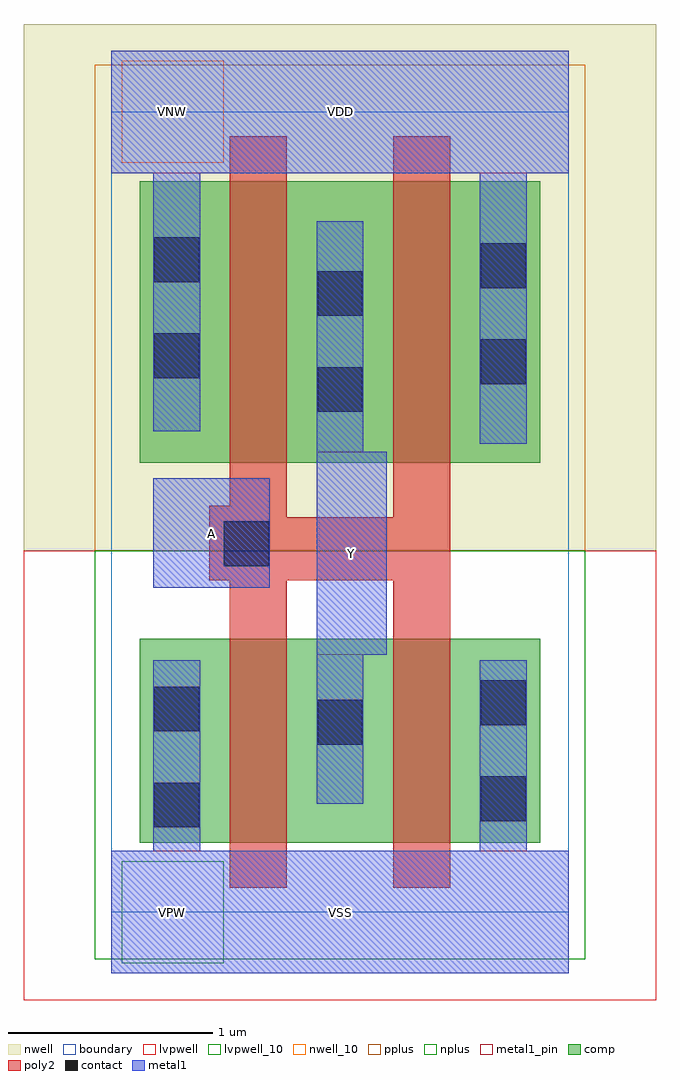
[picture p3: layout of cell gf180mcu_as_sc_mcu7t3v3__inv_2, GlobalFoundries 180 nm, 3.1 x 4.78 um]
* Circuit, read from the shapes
.subckt gf180mcu_as_sc_mcu7t3v3__inv_2 A VDD VNW VSS Y
XM1 Y A VSS VSUBS nfet_03v3 w=1u l=0.28u m=2
XM2 Y A VDD VNW pfet_03v3 w=1.38u l=0.28u m=2
.ends

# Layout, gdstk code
import gdstk
lib = gdstk.Library(unit=1e-6, precision=1e-09)
def R(c, l, rs):  # rectangles x0, y0, x1, y1
    for r in rs: c.add(gdstk.rectangle(r[:2], r[2:], *l))
boundary = (0, 0)
nwell = (21, 0)
nwell_10 = (21, 10)
comp = (22, 0)
poly2 = (30, 0)
pplus = (31, 0)
nplus = (32, 0)
contact = (33, 0)
metal1 = (34, 0)
metal1_pin = (34, 10)
lvpwell = (204, 0)
lvpwell_10 = (204, 10)

gf180mcu_as_sc_mcu7t3v3_ = lib.new_cell('gf180mcu_as_sc_mcu7t3v3__inv_2')
R(gf180mcu_as_sc_mcu7t3v3_, boundary, [(0,0,2.24,3.92)])
R(gf180mcu_as_sc_mcu7t3v3_, nwell, [(-0.43,1.77,2.67,4.35)])
R(gf180mcu_as_sc_mcu7t3v3_, nwell_10, [(0.05,3.67,0.55,4.17)])
R(gf180mcu_as_sc_mcu7t3v3_, comp, [(0.14,0.34,2.1,1.34), (0.14,2.2,2.1,3.58)])
R(gf180mcu_as_sc_mcu7t3v3_, poly2, [(0.58,0.12,0.86,1.625), (1.38,0.12,1.66,1.625), (0.48,1.625,1.66,1.935), (0.48,1.935,0.86,1.99), (1.38,1.935,1.66,3.8), (0.58,1.99,0.86,3.8)])
R(gf180mcu_as_sc_mcu7t3v3_, pplus, [(-0.08,1.77,2.32,4.15), (0.35,1.97,1.89,2.04), (-0.02,2.04,2.26,3.74), (0.35,3.74,1.89,3.81)])
R(gf180mcu_as_sc_mcu7t3v3_, nplus, [(-0.08,-0.23,2.32,1.77), (-0.08,-0.23,2.32,1.77)])
R(gf180mcu_as_sc_mcu7t3v3_, contact, [(0.21,0.415,0.43,0.635), (1.81,0.445,2.03,0.665), (1.01,0.82,1.23,1.04), (0.21,0.885,0.43,1.105), (1.81,0.915,2.03,1.135), (0.55,1.695,0.77,1.915), (1.01,2.45,1.23,2.67), (1.81,2.585,2.03,2.805), (0.21,2.615,0.43,2.835), (1.01,2.92,1.23,3.14), (1.81,3.055,2.03,3.275), (0.21,3.085,0.43,3.305)])
R(gf180mcu_as_sc_mcu7t3v3_, metal1, [(0,-0.3,2.24,0.3), (0.205,0.3,0.435,1.235), (1.805,0.3,2.035,1.235), (1.005,0.53,1.235,1.26), (1.005,1.26,1.35,2.255), (0.205,1.59,0.775,2.125), (1.005,2.255,1.235,3.385), (1.805,2.295,2.035,3.62), (0.205,2.355,0.435,3.62), (0,3.62,2.24,4.22)])
R(gf180mcu_as_sc_mcu7t3v3_, metal1_pin, [(0,-0.3,2.24,0.3), (1.005,1.26,1.35,2.255), (0.205,1.59,0.775,2.125), (0,3.62,2.24,4.22)])
R(gf180mcu_as_sc_mcu7t3v3_, lvpwell, [(-0.43,-0.43,2.67,1.77)])
R(gf180mcu_as_sc_mcu7t3v3_, lvpwell_10, [(0.05,-0.25,0.55,0.25)])
gf180mcu_as_sc_mcu7t3v3_.add(gdstk.Label('VDD', (1.12,3.92), layer=34, texttype=10))
gf180mcu_as_sc_mcu7t3v3_.add(gdstk.Label('VNW', (0.3,3.92), layer=21, texttype=10))
gf180mcu_as_sc_mcu7t3v3_.add(gdstk.Label('VPW', (0.3,0), layer=204, texttype=10))
gf180mcu_as_sc_mcu7t3v3_.add(gdstk.Label('VSS', (1.12,0), layer=34, texttype=10))
gf180mcu_as_sc_mcu7t3v3_.add(gdstk.Label('Y', (1.177,1.757), layer=34, texttype=10))
gf180mcu_as_sc_mcu7t3v3_.add(gdstk.Label('A', (0.49,1.857), layer=34, texttype=10))

lib.write_gds('gf180mcu_as_sc_mcu7t3v3__inv_2.gds')
